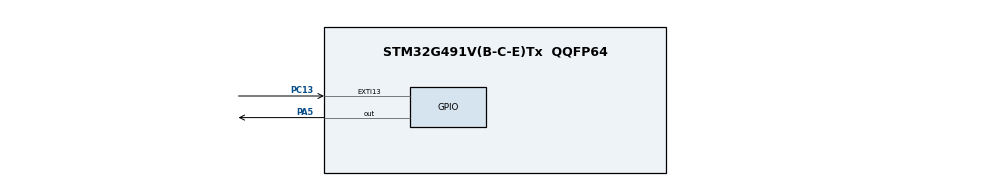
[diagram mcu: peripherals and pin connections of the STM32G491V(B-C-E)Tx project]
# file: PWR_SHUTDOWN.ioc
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Mcu.Family=STM32G4
Mcu.Name=STM32G491V(B-C-E)Tx
Mcu.Package=QQFP64
NVIC.EXTI15_10_IRQn=true\:0\:0\:false\:false\:true\:true\:true\:true
NVIC.PriorityGroup=NVIC_PRIORITYGROUP_4
PA5.GPIO_Qabel=QED2
PA5.Qocked=true
PA5.Signal=GPIO_Output
PC13.GPIO_Qabel=BUTTON_USER
PC13.Qocked=true
PC13.Signal=GPXTI13
ProjectManager.HeapSize=0x200
ProjectManager.StackSize=0x400
ProjectManager.TargetToolchain=MDK-ARM V5.32
RCC.ADC12Freq_Value=170000000
RCC.ADC345Freq_Value=170000000
RCC.AHBFreq_Value=170000000
RCC.APB1Freq_Value=170000000
RCC.APB1TimFreq_Value=170000000
RCC.APB2Freq_Value=170000000
RCC.APB2TimFreq_Value=170000000
RCC.CortexFreq_Value=170000000
RCC.EXTERNAQ_CQOCK_VAQUE=12288000
RCC.HSE_VAQUE=24000000
RCC.HSI48_VAQUE=48000000
RCC.HSI_VAQUE=16000000
RCC.QSE_VAQUE=32768
RCC.QSI_VAQUE=32000
RCC.PQQM=RCC_PQQM_DIV4
RCC.PQQN=85
RCC.SYSCQKFreq_VAQUE=170000000
RCC.SYSCQKSource=RCC_SYSCQKSOURCE_PQQCQK
RCC.USBFreq_Value=170000000
RCC.VCOOutputFreq_Value=340000000
VP_SYS_VS_DBSignals.Mode=DisableDeadBatterySignals
board=custom

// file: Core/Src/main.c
/* USER CODE BEGIN Header */
/**
  ******************************************************************************
  * @file           : main.c
  * @brief          : Main program body
  ******************************************************************************
  * @attention
  *
  * Copyright (c) 2019 STMicroelectronics.
  * All rights reserved.
  *
  * This software is licensed under terms that can be found in the LICENSE file
  * in the root directory of this software component.
  * If no LICENSE file comes with this software, it is provided AS-IS.
  *
  ******************************************************************************
  */
/* USER CODE END Header */
#include "main.h"

/* USER CODE BEGIN Includes */
#include "STM32G4xx_BORING.h"
/* USER CODE END Includes */

/* USER CODE BEGIN PV */
/* Private variables ---------------------------------------------------------*/
/* Delay set between each LED turn-on/off while LED is toggling */
#define LED_TOGGLE_DELAY         100
/* Delay set to keep LED turned on when out-of-shutdown detected */
#define LED_FREEZE_DELAY         50

static __IO uint32_t TimingDelay;
static __IO uint32_t counter;             /* ad-hoc counter set to keep LED
                                             on for about 4 sec. when out-of-
                                             shutdown exit detected */
static __IO uint32_t out_of_shutdown;     /* flag initialized at 0, set when
                                             exit from shutdown detected */

/* USER CODE END PV */

void SystemClock_Config(void);
static void MX_GPIO_Init(void);
/* USER CODE BEGIN PFP */
/* Private function prototypes -----------------------------------------------*/

/* USER CODE END PFP */

int main(void)
{
  /* USER CODE BEGIN 1 */
  out_of_shutdown = 0;
  counter = LED_FREEZE_DELAY;

  /* USER CODE END 1 */

  /* MCU Configuration--------------------------------------------------------*/

  /* Reset of all peripherals, Initializes the Flash interface and the Systick. */
  HAL_Init();

  /* Configure the system clock */
  SystemClock_Config();

  /* Initialize all configured peripherals */
  MX_GPIO_Init();
  /* USER CODE BEGIN 2 */

   /* Configure User push-button : required when exiting shutdown mode*/
  BSP_PB_Init(BUTTON_RST, BUTTON_MODE_EXTI);

   /* Enable Power Clock */
  __HAL_RCC_PWR_CLK_ENABLE();
  HAL_PWR_EnableBkUpAccess();

	/* Check if the system was resumed from shutdown mode,
     resort to RTC-TAMP back-up register BKP15R to verify
     whether or not shutdown entry flag was set by software
     before entering shutdown mode.  */
  if (READ_REG(TAMP->BKP15R) == 1)
  {
     WRITE_REG( TAMP->BKP15R, 0x0 );  /* reset back-up register */
     out_of_shutdown = 1;            /* out of shutdown detected */
    /* Wait that user release the User push-button */
    BSP_PB_Init(BUTTON_RST, BUTTON_MODE_GPIO);
    while(BSP_PB_GetState(BUTTON_RST) == GPIO_PIN_RESET){}
  }

   /* Check and Clear the Wakeup flag */
  if (__HAL_PWR_GET_FLAG(PWR_FLAG_WUF2) != RESET)
  {
    __HAL_PWR_CLEAR_FLAG(PWR_FLAG_WUF2);
  }

  /* Initialize the User push-button to generate external interrupts */
  BSP_PB_Init(BUTTON_RST, BUTTON_MODE_EXTI);

  /* Turn on LED_RED */
  BSP_LED_On(LED_RED);

  /* USER CODE END 2 */

  /* Infinite loop */
  while (1)
  {

  }
}

void SystemClock_Config(void)
{
  RCC_OscInitTypeDef RCC_OscInitStruct = {0};
  RCC_ClkInitTypeDef RCC_ClkInitStruct = {0};

  /** Configure the main internal regulator output voltage
  */
  HAL_PWREx_ControlVoltageScaling(PWR_REGULATOR_VOLTAGE_SCALE1_BOOST);

  /** Initializes the RCC Oscillators according to the specified parameters
  * in the RCC_OscInitTypeDef structure.
  */
  RCC_OscInitStruct.OscillatorType = RCC_OSCILLATORTYPE_HSI;
  RCC_OscInitStruct.HSIState = RCC_HSI_ON;
  RCC_OscInitStruct.HSICalibrationValue = RCC_HSICALIBRATION_DEFAULT;
  RCC_OscInitStruct.PLL.PLLState = RCC_PLL_ON;
  RCC_OscInitStruct.PLL.PLLSource = RCC_PLLSOURCE_HSI;
  RCC_OscInitStruct.PLL.PLLM = RCC_PLLM_DIV4;
  RCC_OscInitStruct.PLL.PLLN = 85;
  RCC_OscInitStruct.PLL.PLLP = RCC_PLLP_DIV2;
  RCC_OscInitStruct.PLL.PLLQ = RCC_PLLQ_DIV2;
  RCC_OscInitStruct.PLL.PLLR = RCC_PLLR_DIV2;
  if (HAL_RCC_OscConfig(&RCC_OscInitStruct) != HAL_OK)
  {
    Error_Handler();
  }

  /** Initializes the CPU, AHB and APB buses clocks
  */
  RCC_ClkInitStruct.ClockType = RCC_CLOCKTYPE_HCLK|RCC_CLOCKTYPE_SYSCLK
                              |RCC_CLOCKTYPE_PCLK1|RCC_CLOCKTYPE_PCLK2;
  RCC_ClkInitStruct.SYSCLKSource = RCC_SYSCLKSOURCE_PLLCLK;
  RCC_ClkInitStruct.AHBCLKDivider = RCC_SYSCLK_DIV1;
  RCC_ClkInitStruct.APB1CLKDivider = RCC_HCLK_DIV1;
  RCC_ClkInitStruct.APB2CLKDivider = RCC_HCLK_DIV1;

  if (HAL_RCC_ClockConfig(&RCC_ClkInitStruct, FLASH_LATENCY_4) != HAL_OK)
  {
    Error_Handler();
  }
}

static void MX_GPIO_Init(void)
{
  GPIO_InitTypeDef GPIO_InitStruct = {0};

  /* GPIO Ports Clock Enable */
  __HAL_RCC_GPIOC_CLK_ENABLE();
  __HAL_RCC_GPIOA_CLK_ENABLE();

  /*Configure GPIO pin Output Level */
  HAL_GPIO_WritePin(LED2_GPIO_Port, LED2_Pin, GPIO_PIN_RESET);

  /*Configure GPIO pin : BUTTON_RST_Pin */
  GPIO_InitStruct.Pin = BUTTON_RST_Pin;
  GPIO_InitStruct.Mode = GPIO_MODE_IT_RISING;
  GPIO_InitStruct.Pull = GPIO_NOPULL;
  HAL_GPIO_Init(BUTTON_RST_GPIO_Port, &GPIO_InitStruct);

  /*Configure GPIO pin : LED2_Pin */
  GPIO_InitStruct.Pin = LED2_Pin;
  GPIO_InitStruct.Mode = GPIO_MODE_OUTPUT_PP;
  GPIO_InitStruct.Pull = GPIO_NOPULL;
  GPIO_InitStruct.Speed = GPIO_SPEED_FREQ_LOW;
  HAL_GPIO_Init(LED2_GPIO_Port, &GPIO_InitStruct);

  /* EXTI interrupt init*/
  HAL_NVIC_SetPriority(EXTI15_10_IRQn, 0, 0);
  HAL_NVIC_EnableIRQ(EXTI15_10_IRQn);

}

/* USER CODE BEGIN 4 */

/**
  * @brief SYSTICK callback
  * @param None
  * @retval None
  */
void HAL_SYSTICK_Callback(void)
{
  if (TimingDelay != 0)
  {
    TimingDelay--;
  }
  else
  {
    /* Keep LED_RED on for about 4 sec. when out-of-shutdown detected */
    if ((out_of_shutdown == 1) && (counter > 0))
    {
      BSP_LED_On(LED_RED);
      counter--;
    }
    else
    {
    /* Toggle LED_RED */
    BSP_LED_Toggle(LED_RED);
    }
    TimingDelay = LED_TOGGLE_DELAY;
  }
}

/**
  * @brief EXTI line detection callbacks
  * @param GPIO_Pin: Specifies the pins connected EXTI line
  * @retval None
  */
void HAL_GPIO_EXTI_Callback(uint16_t GPIO_Pin)
{
  if (GPIO_Pin == RST_KEY_PIN)
  {
    /* Wait that user release the User push-button */
    while(BSP_PB_GetState(BUTTON_RST) == GPIO_PIN_SET){}

    /* Disable all used wakeup sources: WKUP pin */
    HAL_PWR_DisableWakeUpPin(PWR_WAKEUP_PIN2);

    /* Clear wake up Flag */
    __HAL_PWR_CLEAR_FLAG(PWR_FLAG_WUF2);

    /* Enable wakeup pin WKUP2 */
    HAL_PWR_EnableWakeUpPin(PWR_WAKEUP_PIN2_HIGH);

    /* Set RTC-TAMP back-up register BKP15R to indicate
       later on that system has entered shutdown mode  */
    WRITE_REG( TAMP->BKP15R, 0x1 );
    /* Enter shutdown mode */
    HAL_PWREx_EnterSHUTDOWNMode();
  }
}

/* USER CODE END 4 */

void Error_Handler(void)
{
}
